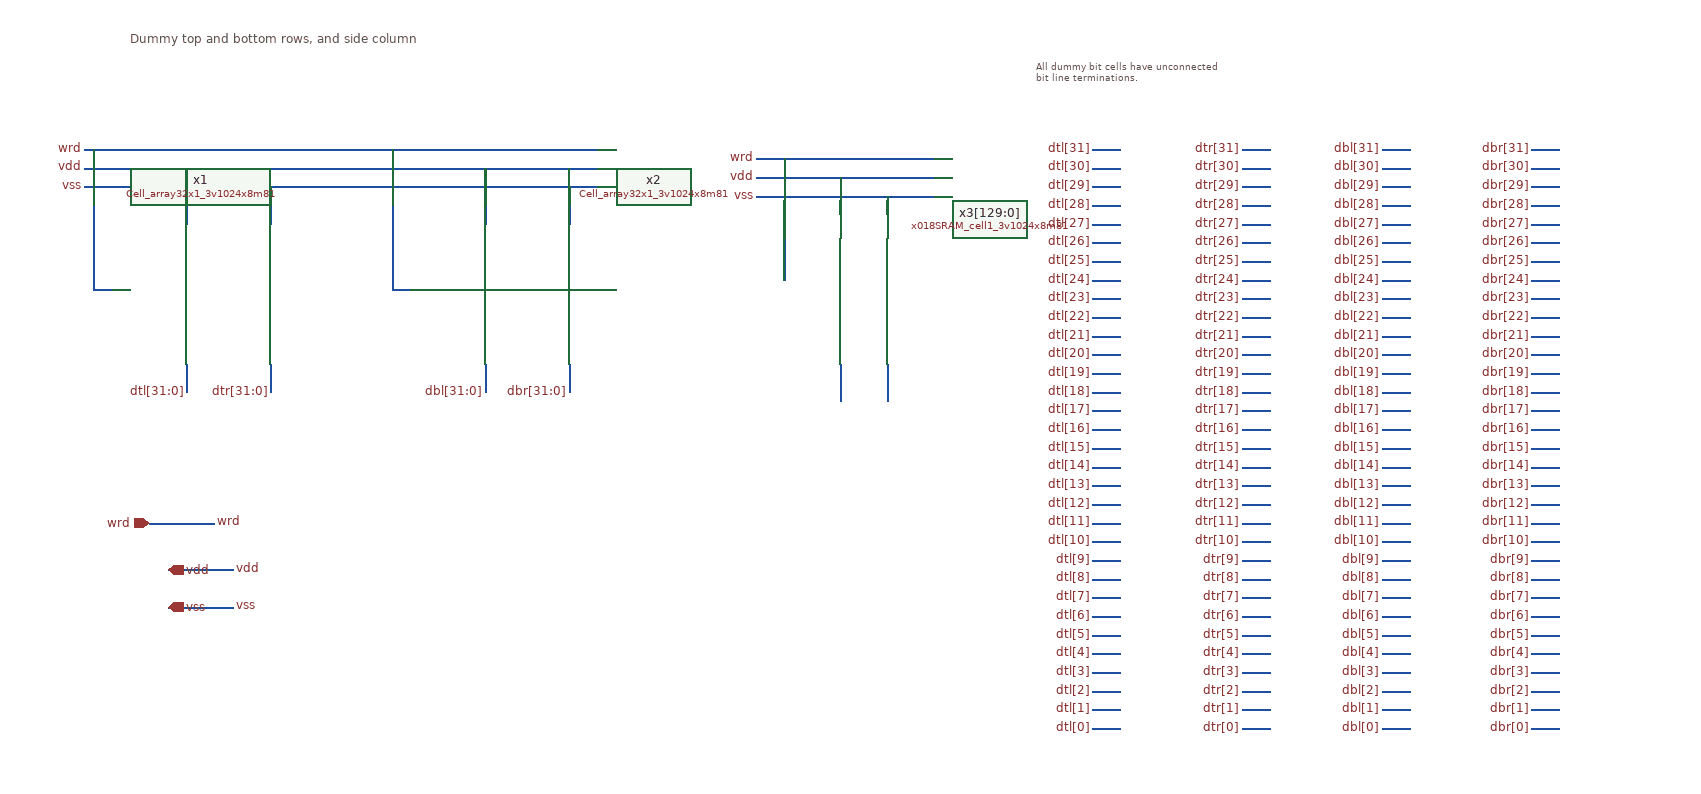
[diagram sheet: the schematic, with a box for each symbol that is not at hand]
v {xschem version=3.4.6 file_version=1.2}
G {}
K {}
V {}
S {}
E {}
T {Dummy top and bottom rows, and side column} -160 -200 0 0 0.4 0.4 {}
T {All dummy bit cells have unconnected
bit line terminations.} 810 -170 0 0 0.3 0.3 {}
N 310 -30 310 10 {lab=vss}
N 220 -50 220 10 {lab=vdd}
N -10 -30 -10 10 {lab=vss}
N -100 -50 -100 10 {lab=vdd}
N -200 80 -180 80 {lab=wrd}
N -200 -70 -200 80 {lab=wrd}
N 120 80 140 80 {lab=wrd}
N 120 -70 120 80 {lab=wrd}
N -100 160 -100 190 {lab=dtl[31:0]}
N -10 160 -10 190 {lab=dtr[31:0]}
N 220 160 220 190 {lab=dbl[31:0]}
N 310 160 310 190 {lab=dbr[31:0]}
N -140 330 -70 330 {lab=wrd}
N -120 380 -50 380 {lab=vdd}
N -120 420 -50 420 {lab=vss}
N -210 -50 340 -50 {lab=vdd}
N -210 -30 340 -30 {lab=vss}
N 540 -60 540 70 {lab=wrd}
N 600 -40 600 0 {lab=vdd}
N 600 160 600 200 {lab=#net1}
N 650 160 650 200 {lab=#net2}
N 510 -20 700 -20 {lab=vss}
N 650 -20 650 0 {lab=vss}
N 510 -40 700 -40 {lab=vdd}
N 510 -60 700 -60 {lab=wrd}
N -210 -70 340 -70 {lab=wrd}
N 870 -70 900 -70 {lab=dtl[31]}
N 870 -50 900 -50 {lab=dtl[30]}
N 870 -30 900 -30 {lab=dtl[29]}
N 870 -10 900 -10 {lab=dtl[28]}
N 870 10 900 10 {lab=dtl[27]}
N 870 30 900 30 {lab=dtl[26]}
N 870 50 900 50 {lab=dtl[25]}
N 870 70 900 70 {lab=dtl[24]}
N 870 90 900 90 {lab=dtl[23]}
N 870 110 900 110 {lab=dtl[22]}
N 870 130 900 130 {lab=dtl[21]}
N 870 150 900 150 {lab=dtl[20]}
N 870 170 900 170 {lab=dtl[19]}
N 870 190 900 190 {lab=dtl[18]}
N 870 210 900 210 {lab=dtl[17]}
N 870 230 900 230 {lab=dtl[16]}
N 870 250 900 250 {lab=dtl[15]}
N 870 270 900 270 {lab=dtl[14]}
N 870 290 900 290 {lab=dtl[13]}
N 870 310 900 310 {lab=dtl[12]}
N 870 330 900 330 {lab=dtl[11]}
N 870 350 900 350 {lab=dtl[10]}
N 870 370 900 370 {lab=dtl[9]}
N 870 390 900 390 {lab=dtl[8]}
N 870 410 900 410 {lab=dtl[7]}
N 870 430 900 430 {lab=dtl[6]}
N 870 450 900 450 {lab=dtl[5]}
N 870 470 900 470 {lab=dtl[4]}
N 870 490 900 490 {lab=dtl[3]}
N 870 510 900 510 {lab=dtl[2]}
N 870 530 900 530 {lab=dtl[1]}
N 870 550 900 550 {lab=dtl[0]}
N 1030 -70 1060 -70 {lab=dtr[31]}
N 1030 -50 1060 -50 {lab=dtr[30]}
N 1030 -30 1060 -30 {lab=dtr[29]}
N 1030 -10 1060 -10 {lab=dtr[28]}
N 1030 10 1060 10 {lab=dtr[27]}
N 1030 30 1060 30 {lab=dtr[26]}
N 1030 50 1060 50 {lab=dtr[25]}
N 1030 70 1060 70 {lab=dtr[24]}
N 1030 90 1060 90 {lab=dtr[23]}
N 1030 110 1060 110 {lab=dtr[22]}
N 1030 130 1060 130 {lab=dtr[21]}
N 1030 150 1060 150 {lab=dtr[20]}
N 1030 170 1060 170 {lab=dtr[19]}
N 1030 190 1060 190 {lab=dtr[18]}
N 1030 210 1060 210 {lab=dtr[17]}
N 1030 230 1060 230 {lab=dtr[16]}
N 1030 250 1060 250 {lab=dtr[15]}
N 1030 270 1060 270 {lab=dtr[14]}
N 1030 290 1060 290 {lab=dtr[13]}
N 1030 310 1060 310 {lab=dtr[12]}
N 1030 330 1060 330 {lab=dtr[11]}
N 1030 350 1060 350 {lab=dtr[10]}
N 1030 370 1060 370 {lab=dtr[9]}
N 1030 390 1060 390 {lab=dtr[8]}
N 1030 410 1060 410 {lab=dtr[7]}
N 1030 430 1060 430 {lab=dtr[6]}
N 1030 450 1060 450 {lab=dtr[5]}
N 1030 470 1060 470 {lab=dtr[4]}
N 1030 490 1060 490 {lab=dtr[3]}
N 1030 510 1060 510 {lab=dtr[2]}
N 1030 530 1060 530 {lab=dtr[1]}
N 1030 550 1060 550 {lab=dtr[0]}
N 1180 -70 1210 -70 {lab=dbl[31]}
N 1180 -50 1210 -50 {lab=dbl[30]}
N 1180 -30 1210 -30 {lab=dbl[29]}
N 1180 -10 1210 -10 {lab=dbl[28]}
N 1180 10 1210 10 {lab=dbl[27]}
N 1180 30 1210 30 {lab=dbl[26]}
N 1180 50 1210 50 {lab=dbl[25]}
N 1180 70 1210 70 {lab=dbl[24]}
N 1180 90 1210 90 {lab=dbl[23]}
N 1180 110 1210 110 {lab=dbl[22]}
N 1180 130 1210 130 {lab=dbl[21]}
N 1180 150 1210 150 {lab=dbl[20]}
N 1180 170 1210 170 {lab=dbl[19]}
N 1180 190 1210 190 {lab=dbl[18]}
N 1180 210 1210 210 {lab=dbl[17]}
N 1180 230 1210 230 {lab=dbl[16]}
N 1180 250 1210 250 {lab=dbl[15]}
N 1180 270 1210 270 {lab=dbl[14]}
N 1180 290 1210 290 {lab=dbl[13]}
N 1180 310 1210 310 {lab=dbl[12]}
N 1180 330 1210 330 {lab=dbl[11]}
N 1180 350 1210 350 {lab=dbl[10]}
N 1180 370 1210 370 {lab=dbl[9]}
N 1180 390 1210 390 {lab=dbl[8]}
N 1180 410 1210 410 {lab=dbl[7]}
N 1180 430 1210 430 {lab=dbl[6]}
N 1180 450 1210 450 {lab=dbl[5]}
N 1180 470 1210 470 {lab=dbl[4]}
N 1180 490 1210 490 {lab=dbl[3]}
N 1180 510 1210 510 {lab=dbl[2]}
N 1180 530 1210 530 {lab=dbl[1]}
N 1180 550 1210 550 {lab=dbl[0]}
N 1340 -70 1370 -70 {lab=dbr[31]}
N 1340 -50 1370 -50 {lab=dbr[30]}
N 1340 -30 1370 -30 {lab=dbr[29]}
N 1340 -10 1370 -10 {lab=dbr[28]}
N 1340 10 1370 10 {lab=dbr[27]}
N 1340 30 1370 30 {lab=dbr[26]}
N 1340 50 1370 50 {lab=dbr[25]}
N 1340 70 1370 70 {lab=dbr[24]}
N 1340 90 1370 90 {lab=dbr[23]}
N 1340 110 1370 110 {lab=dbr[22]}
N 1340 130 1370 130 {lab=dbr[21]}
N 1340 150 1370 150 {lab=dbr[20]}
N 1340 170 1370 170 {lab=dbr[19]}
N 1340 190 1370 190 {lab=dbr[18]}
N 1340 210 1370 210 {lab=dbr[17]}
N 1340 230 1370 230 {lab=dbr[16]}
N 1340 250 1370 250 {lab=dbr[15]}
N 1340 270 1370 270 {lab=dbr[14]}
N 1340 290 1370 290 {lab=dbr[13]}
N 1340 310 1370 310 {lab=dbr[12]}
N 1340 330 1370 330 {lab=dbr[11]}
N 1340 350 1370 350 {lab=dbr[10]}
N 1340 370 1370 370 {lab=dbr[9]}
N 1340 390 1370 390 {lab=dbr[8]}
N 1340 410 1370 410 {lab=dbr[7]}
N 1340 430 1370 430 {lab=dbr[6]}
N 1340 450 1370 450 {lab=dbr[5]}
N 1340 470 1370 470 {lab=dbr[4]}
N 1340 490 1370 490 {lab=dbr[3]}
N 1340 510 1370 510 {lab=dbr[2]}
N 1340 530 1370 530 {lab=dbr[1]}
N 1340 550 1370 550 {lab=dbr[0]}
C {Cell_array32x1_3v1024x8m81.sym} -50 80 0 0 {name=x1}
C {Cell_array32x1_3v1024x8m81.sym} 270 80 0 0 {name=x2}
C {lab_pin.sym} -210 -50 0 0 {name=p97 sig_type=std_logic lab=vdd}
C {lab_pin.sym} -210 -30 0 0 {name=p98 sig_type=std_logic lab=vss}
C {ipin.sym} -140 330 0 0 {name=p105 lab=wrd}
C {iopin.sym} -120 380 0 1 {name=p108 lab=vdd}
C {iopin.sym} -120 420 0 1 {name=p109 lab=vss}
C {lab_pin.sym} -50 420 0 1 {name=p110 sig_type=std_logic lab=vss}
C {lab_pin.sym} -50 380 0 1 {name=p111 sig_type=std_logic lab=vdd}
C {lab_pin.sym} -70 330 0 1 {name=p114 sig_type=std_logic lab=wrd}
C {x018SRAM_cell1_3v1024x8m81.sym} 690 50 0 0 {name=x3[129:0]}
C {lab_pin.sym} 510 -20 0 0 {name=p5 sig_type=std_logic lab=vss}
C {lab_pin.sym} 510 -40 0 0 {name=p6 sig_type=std_logic lab=vdd}
C {lab_pin.sym} 510 -60 0 0 {name=p9 sig_type=std_logic lab=wrd}
C {lab_pin.sym} -210 -70 0 0 {name=p10 sig_type=std_logic lab=wrd}
C {noconn.sym} 650 200 3 0 {name=l1}
C {noconn.sym} 600 200 3 0 {name=l2}
C {lab_pin.sym} -100 190 3 0 {name=p1 sig_type=std_logic lab=dtl[31:0]}
C {lab_pin.sym} -10 190 3 0 {name=p2 sig_type=std_logic lab=dtr[31:0]}
C {lab_pin.sym} 220 190 3 0 {name=p3 sig_type=std_logic lab=dbl[31:0]}
C {lab_pin.sym} 310 190 3 0 {name=p4 sig_type=std_logic lab=dbr[31:0]}
C {noconn.sym} 900 -70 0 1 {name=l3}
C {noconn.sym} 900 -50 0 1 {name=l4}
C {noconn.sym} 900 -30 0 1 {name=l5}
C {noconn.sym} 900 -10 0 1 {name=l6}
C {noconn.sym} 900 10 0 1 {name=l7}
C {noconn.sym} 900 30 0 1 {name=l8}
C {noconn.sym} 900 50 0 1 {name=l9}
C {noconn.sym} 900 70 0 1 {name=l10}
C {noconn.sym} 900 90 0 1 {name=l11}
C {noconn.sym} 900 110 0 1 {name=l12}
C {noconn.sym} 900 130 0 1 {name=l13}
C {noconn.sym} 900 150 0 1 {name=l14}
C {noconn.sym} 900 170 0 1 {name=l15}
C {noconn.sym} 900 190 0 1 {name=l16}
C {noconn.sym} 900 210 0 1 {name=l17}
C {noconn.sym} 900 230 0 1 {name=l18}
C {noconn.sym} 900 250 0 1 {name=l19}
C {noconn.sym} 900 270 0 1 {name=l20}
C {noconn.sym} 900 290 0 1 {name=l21}
C {noconn.sym} 900 310 0 1 {name=l22}
C {noconn.sym} 900 330 0 1 {name=l23}
C {noconn.sym} 900 350 0 1 {name=l24}
C {noconn.sym} 900 370 0 1 {name=l25}
C {noconn.sym} 900 390 0 1 {name=l26}
C {noconn.sym} 900 410 0 1 {name=l27}
C {noconn.sym} 900 430 0 1 {name=l28}
C {noconn.sym} 900 450 0 1 {name=l29}
C {noconn.sym} 900 470 0 1 {name=l30}
C {noconn.sym} 900 490 0 1 {name=l31}
C {noconn.sym} 900 510 0 1 {name=l32}
C {noconn.sym} 900 530 0 1 {name=l33}
C {noconn.sym} 900 550 0 1 {name=l34}
C {lab_pin.sym} 870 -70 0 0 {name=p7 sig_type=std_logic lab=dtl[31]}
C {lab_pin.sym} 870 -50 0 0 {name=p8 sig_type=std_logic lab=dtl[30]}
C {lab_pin.sym} 870 -30 0 0 {name=p11 sig_type=std_logic lab=dtl[29]}
C {lab_pin.sym} 870 -10 0 0 {name=p12 sig_type=std_logic lab=dtl[28]}
C {lab_pin.sym} 870 10 0 0 {name=p13 sig_type=std_logic lab=dtl[27]}
C {lab_pin.sym} 870 30 0 0 {name=p14 sig_type=std_logic lab=dtl[26]}
C {lab_pin.sym} 870 50 0 0 {name=p15 sig_type=std_logic lab=dtl[25]}
C {lab_pin.sym} 870 70 0 0 {name=p16 sig_type=std_logic lab=dtl[24]}
C {lab_pin.sym} 870 90 0 0 {name=p17 sig_type=std_logic lab=dtl[23]}
C {lab_pin.sym} 870 110 0 0 {name=p18 sig_type=std_logic lab=dtl[22]}
C {lab_pin.sym} 870 130 0 0 {name=p19 sig_type=std_logic lab=dtl[21]}
C {lab_pin.sym} 870 150 0 0 {name=p20 sig_type=std_logic lab=dtl[20]}
C {lab_pin.sym} 870 170 0 0 {name=p21 sig_type=std_logic lab=dtl[19]}
C {lab_pin.sym} 870 190 0 0 {name=p22 sig_type=std_logic lab=dtl[18]}
C {lab_pin.sym} 870 210 0 0 {name=p23 sig_type=std_logic lab=dtl[17]}
C {lab_pin.sym} 870 230 0 0 {name=p24 sig_type=std_logic lab=dtl[16]}
C {lab_pin.sym} 870 250 0 0 {name=p25 sig_type=std_logic lab=dtl[15]}
C {lab_pin.sym} 870 270 0 0 {name=p26 sig_type=std_logic lab=dtl[14]}
C {lab_pin.sym} 870 290 0 0 {name=p27 sig_type=std_logic lab=dtl[13]}
C {lab_pin.sym} 870 310 0 0 {name=p28 sig_type=std_logic lab=dtl[12]}
C {lab_pin.sym} 870 330 0 0 {name=p29 sig_type=std_logic lab=dtl[11]}
C {lab_pin.sym} 870 350 0 0 {name=p30 sig_type=std_logic lab=dtl[10]}
C {lab_pin.sym} 870 370 0 0 {name=p31 sig_type=std_logic lab=dtl[9]}
C {lab_pin.sym} 870 390 0 0 {name=p32 sig_type=std_logic lab=dtl[8]}
C {lab_pin.sym} 870 410 0 0 {name=p33 sig_type=std_logic lab=dtl[7]}
C {lab_pin.sym} 870 430 0 0 {name=p34 sig_type=std_logic lab=dtl[6]}
C {lab_pin.sym} 870 450 0 0 {name=p35 sig_type=std_logic lab=dtl[5]}
C {lab_pin.sym} 870 470 0 0 {name=p36 sig_type=std_logic lab=dtl[4]}
C {lab_pin.sym} 870 490 0 0 {name=p37 sig_type=std_logic lab=dtl[3]}
C {lab_pin.sym} 870 510 0 0 {name=p38 sig_type=std_logic lab=dtl[2]}
C {lab_pin.sym} 870 530 0 0 {name=p39 sig_type=std_logic lab=dtl[1]}
C {lab_pin.sym} 870 550 0 0 {name=p40 sig_type=std_logic lab=dtl[0]}
C {noconn.sym} 1060 -70 0 1 {name=l35}
C {noconn.sym} 1060 -50 0 1 {name=l36}
C {noconn.sym} 1060 -30 0 1 {name=l37}
C {noconn.sym} 1060 -10 0 1 {name=l38}
C {noconn.sym} 1060 10 0 1 {name=l39}
C {noconn.sym} 1060 30 0 1 {name=l40}
C {noconn.sym} 1060 50 0 1 {name=l41}
C {noconn.sym} 1060 70 0 1 {name=l42}
C {noconn.sym} 1060 90 0 1 {name=l43}
C {noconn.sym} 1060 110 0 1 {name=l44}
C {noconn.sym} 1060 130 0 1 {name=l45}
C {noconn.sym} 1060 150 0 1 {name=l46}
C {noconn.sym} 1060 170 0 1 {name=l47}
C {noconn.sym} 1060 190 0 1 {name=l48}
C {noconn.sym} 1060 210 0 1 {name=l49}
C {noconn.sym} 1060 230 0 1 {name=l50}
C {noconn.sym} 1060 250 0 1 {name=l51}
C {noconn.sym} 1060 270 0 1 {name=l52}
C {noconn.sym} 1060 290 0 1 {name=l53}
C {noconn.sym} 1060 310 0 1 {name=l54}
C {noconn.sym} 1060 330 0 1 {name=l55}
C {noconn.sym} 1060 350 0 1 {name=l56}
C {noconn.sym} 1060 370 0 1 {name=l57}
C {noconn.sym} 1060 390 0 1 {name=l58}
C {noconn.sym} 1060 410 0 1 {name=l59}
C {noconn.sym} 1060 430 0 1 {name=l60}
C {noconn.sym} 1060 450 0 1 {name=l61}
C {noconn.sym} 1060 470 0 1 {name=l62}
C {noconn.sym} 1060 490 0 1 {name=l63}
C {noconn.sym} 1060 510 0 1 {name=l64}
C {noconn.sym} 1060 530 0 1 {name=l65}
C {noconn.sym} 1060 550 0 1 {name=l66}
C {lab_pin.sym} 1030 -70 0 0 {name=p41 sig_type=std_logic lab=dtr[31]}
C {lab_pin.sym} 1030 -50 0 0 {name=p42 sig_type=std_logic lab=dtr[30]}
C {lab_pin.sym} 1030 -30 0 0 {name=p43 sig_type=std_logic lab=dtr[29]}
C {lab_pin.sym} 1030 -10 0 0 {name=p44 sig_type=std_logic lab=dtr[28]}
C {lab_pin.sym} 1030 10 0 0 {name=p45 sig_type=std_logic lab=dtr[27]}
C {lab_pin.sym} 1030 30 0 0 {name=p46 sig_type=std_logic lab=dtr[26]}
C {lab_pin.sym} 1030 50 0 0 {name=p47 sig_type=std_logic lab=dtr[25]}
C {lab_pin.sym} 1030 70 0 0 {name=p48 sig_type=std_logic lab=dtr[24]}
C {lab_pin.sym} 1030 90 0 0 {name=p49 sig_type=std_logic lab=dtr[23]}
C {lab_pin.sym} 1030 110 0 0 {name=p50 sig_type=std_logic lab=dtr[22]}
C {lab_pin.sym} 1030 130 0 0 {name=p51 sig_type=std_logic lab=dtr[21]}
C {lab_pin.sym} 1030 150 0 0 {name=p52 sig_type=std_logic lab=dtr[20]}
C {lab_pin.sym} 1030 170 0 0 {name=p53 sig_type=std_logic lab=dtr[19]}
C {lab_pin.sym} 1030 190 0 0 {name=p54 sig_type=std_logic lab=dtr[18]}
C {lab_pin.sym} 1030 210 0 0 {name=p55 sig_type=std_logic lab=dtr[17]}
C {lab_pin.sym} 1030 230 0 0 {name=p56 sig_type=std_logic lab=dtr[16]}
C {lab_pin.sym} 1030 250 0 0 {name=p57 sig_type=std_logic lab=dtr[15]}
C {lab_pin.sym} 1030 270 0 0 {name=p58 sig_type=std_logic lab=dtr[14]}
C {lab_pin.sym} 1030 290 0 0 {name=p59 sig_type=std_logic lab=dtr[13]}
C {lab_pin.sym} 1030 310 0 0 {name=p60 sig_type=std_logic lab=dtr[12]}
C {lab_pin.sym} 1030 330 0 0 {name=p61 sig_type=std_logic lab=dtr[11]}
C {lab_pin.sym} 1030 350 0 0 {name=p62 sig_type=std_logic lab=dtr[10]}
C {lab_pin.sym} 1030 370 0 0 {name=p63 sig_type=std_logic lab=dtr[9]}
C {lab_pin.sym} 1030 390 0 0 {name=p64 sig_type=std_logic lab=dtr[8]}
C {lab_pin.sym} 1030 410 0 0 {name=p65 sig_type=std_logic lab=dtr[7]}
C {lab_pin.sym} 1030 430 0 0 {name=p66 sig_type=std_logic lab=dtr[6]}
C {lab_pin.sym} 1030 450 0 0 {name=p67 sig_type=std_logic lab=dtr[5]}
C {lab_pin.sym} 1030 470 0 0 {name=p68 sig_type=std_logic lab=dtr[4]}
C {lab_pin.sym} 1030 490 0 0 {name=p69 sig_type=std_logic lab=dtr[3]}
C {lab_pin.sym} 1030 510 0 0 {name=p70 sig_type=std_logic lab=dtr[2]}
C {lab_pin.sym} 1030 530 0 0 {name=p71 sig_type=std_logic lab=dtr[1]}
C {lab_pin.sym} 1030 550 0 0 {name=p72 sig_type=std_logic lab=dtr[0]}
C {noconn.sym} 1210 -70 0 1 {name=l67}
C {noconn.sym} 1210 -50 0 1 {name=l68}
C {noconn.sym} 1210 -30 0 1 {name=l69}
C {noconn.sym} 1210 -10 0 1 {name=l70}
C {noconn.sym} 1210 10 0 1 {name=l71}
C {noconn.sym} 1210 30 0 1 {name=l72}
C {noconn.sym} 1210 50 0 1 {name=l73}
C {noconn.sym} 1210 70 0 1 {name=l74}
C {noconn.sym} 1210 90 0 1 {name=l75}
C {noconn.sym} 1210 110 0 1 {name=l76}
C {noconn.sym} 1210 130 0 1 {name=l77}
C {noconn.sym} 1210 150 0 1 {name=l78}
C {noconn.sym} 1210 170 0 1 {name=l79}
C {noconn.sym} 1210 190 0 1 {name=l80}
C {noconn.sym} 1210 210 0 1 {name=l81}
C {noconn.sym} 1210 230 0 1 {name=l82}
C {noconn.sym} 1210 250 0 1 {name=l83}
C {noconn.sym} 1210 270 0 1 {name=l84}
C {noconn.sym} 1210 290 0 1 {name=l85}
C {noconn.sym} 1210 310 0 1 {name=l86}
C {noconn.sym} 1210 330 0 1 {name=l87}
C {noconn.sym} 1210 350 0 1 {name=l88}
C {noconn.sym} 1210 370 0 1 {name=l89}
C {noconn.sym} 1210 390 0 1 {name=l90}
C {noconn.sym} 1210 410 0 1 {name=l91}
C {noconn.sym} 1210 430 0 1 {name=l92}
C {noconn.sym} 1210 450 0 1 {name=l93}
C {noconn.sym} 1210 470 0 1 {name=l94}
C {noconn.sym} 1210 490 0 1 {name=l95}
C {noconn.sym} 1210 510 0 1 {name=l96}
C {noconn.sym} 1210 530 0 1 {name=l97}
C {noconn.sym} 1210 550 0 1 {name=l98}
C {lab_pin.sym} 1180 -70 0 0 {name=p73 sig_type=std_logic lab=dbl[31]}
C {lab_pin.sym} 1180 -50 0 0 {name=p74 sig_type=std_logic lab=dbl[30]}
C {lab_pin.sym} 1180 -30 0 0 {name=p75 sig_type=std_logic lab=dbl[29]}
C {lab_pin.sym} 1180 -10 0 0 {name=p76 sig_type=std_logic lab=dbl[28]}
C {lab_pin.sym} 1180 10 0 0 {name=p77 sig_type=std_logic lab=dbl[27]}
C {lab_pin.sym} 1180 30 0 0 {name=p78 sig_type=std_logic lab=dbl[26]}
C {lab_pin.sym} 1180 50 0 0 {name=p79 sig_type=std_logic lab=dbl[25]}
C {lab_pin.sym} 1180 70 0 0 {name=p80 sig_type=std_logic lab=dbl[24]}
C {lab_pin.sym} 1180 90 0 0 {name=p81 sig_type=std_logic lab=dbl[23]}
C {lab_pin.sym} 1180 110 0 0 {name=p82 sig_type=std_logic lab=dbl[22]}
C {lab_pin.sym} 1180 130 0 0 {name=p83 sig_type=std_logic lab=dbl[21]}
C {lab_pin.sym} 1180 150 0 0 {name=p84 sig_type=std_logic lab=dbl[20]}
C {lab_pin.sym} 1180 170 0 0 {name=p85 sig_type=std_logic lab=dbl[19]}
C {lab_pin.sym} 1180 190 0 0 {name=p86 sig_type=std_logic lab=dbl[18]}
C {lab_pin.sym} 1180 210 0 0 {name=p87 sig_type=std_logic lab=dbl[17]}
C {lab_pin.sym} 1180 230 0 0 {name=p88 sig_type=std_logic lab=dbl[16]}
C {lab_pin.sym} 1180 250 0 0 {name=p89 sig_type=std_logic lab=dbl[15]}
C {lab_pin.sym} 1180 270 0 0 {name=p90 sig_type=std_logic lab=dbl[14]}
C {lab_pin.sym} 1180 290 0 0 {name=p91 sig_type=std_logic lab=dbl[13]}
C {lab_pin.sym} 1180 310 0 0 {name=p92 sig_type=std_logic lab=dbl[12]}
C {lab_pin.sym} 1180 330 0 0 {name=p93 sig_type=std_logic lab=dbl[11]}
C {lab_pin.sym} 1180 350 0 0 {name=p94 sig_type=std_logic lab=dbl[10]}
C {lab_pin.sym} 1180 370 0 0 {name=p95 sig_type=std_logic lab=dbl[9]}
C {lab_pin.sym} 1180 390 0 0 {name=p96 sig_type=std_logic lab=dbl[8]}
C {lab_pin.sym} 1180 410 0 0 {name=p99 sig_type=std_logic lab=dbl[7]}
C {lab_pin.sym} 1180 430 0 0 {name=p100 sig_type=std_logic lab=dbl[6]}
C {lab_pin.sym} 1180 450 0 0 {name=p101 sig_type=std_logic lab=dbl[5]}
C {lab_pin.sym} 1180 470 0 0 {name=p102 sig_type=std_logic lab=dbl[4]}
C {lab_pin.sym} 1180 490 0 0 {name=p103 sig_type=std_logic lab=dbl[3]}
C {lab_pin.sym} 1180 510 0 0 {name=p104 sig_type=std_logic lab=dbl[2]}
C {lab_pin.sym} 1180 530 0 0 {name=p106 sig_type=std_logic lab=dbl[1]}
C {lab_pin.sym} 1180 550 0 0 {name=p107 sig_type=std_logic lab=dbl[0]}
C {noconn.sym} 1370 -70 0 1 {name=l99}
C {noconn.sym} 1370 -50 0 1 {name=l100}
C {noconn.sym} 1370 -30 0 1 {name=l101}
C {noconn.sym} 1370 -10 0 1 {name=l102}
C {noconn.sym} 1370 10 0 1 {name=l103}
C {noconn.sym} 1370 30 0 1 {name=l104}
C {noconn.sym} 1370 50 0 1 {name=l105}
C {noconn.sym} 1370 70 0 1 {name=l106}
C {noconn.sym} 1370 90 0 1 {name=l107}
C {noconn.sym} 1370 110 0 1 {name=l108}
C {noconn.sym} 1370 130 0 1 {name=l109}
C {noconn.sym} 1370 150 0 1 {name=l110}
C {noconn.sym} 1370 170 0 1 {name=l111}
C {noconn.sym} 1370 190 0 1 {name=l112}
C {noconn.sym} 1370 210 0 1 {name=l113}
C {noconn.sym} 1370 230 0 1 {name=l114}
C {noconn.sym} 1370 250 0 1 {name=l115}
C {noconn.sym} 1370 270 0 1 {name=l116}
C {noconn.sym} 1370 290 0 1 {name=l117}
C {noconn.sym} 1370 310 0 1 {name=l118}
C {noconn.sym} 1370 330 0 1 {name=l119}
C {noconn.sym} 1370 350 0 1 {name=l120}
C {noconn.sym} 1370 370 0 1 {name=l121}
C {noconn.sym} 1370 390 0 1 {name=l122}
C {noconn.sym} 1370 410 0 1 {name=l123}
C {noconn.sym} 1370 430 0 1 {name=l124}
C {noconn.sym} 1370 450 0 1 {name=l125}
C {noconn.sym} 1370 470 0 1 {name=l126}
C {noconn.sym} 1370 490 0 1 {name=l127}
C {noconn.sym} 1370 510 0 1 {name=l128}
C {noconn.sym} 1370 530 0 1 {name=l129}
C {noconn.sym} 1370 550 0 1 {name=l130}
C {lab_pin.sym} 1340 -70 0 0 {name=p112 sig_type=std_logic lab=dbr[31]}
C {lab_pin.sym} 1340 -50 0 0 {name=p113 sig_type=std_logic lab=dbr[30]}
C {lab_pin.sym} 1340 -30 0 0 {name=p115 sig_type=std_logic lab=dbr[29]}
C {lab_pin.sym} 1340 -10 0 0 {name=p116 sig_type=std_logic lab=dbr[28]}
C {lab_pin.sym} 1340 10 0 0 {name=p117 sig_type=std_logic lab=dbr[27]}
C {lab_pin.sym} 1340 30 0 0 {name=p118 sig_type=std_logic lab=dbr[26]}
C {lab_pin.sym} 1340 50 0 0 {name=p119 sig_type=std_logic lab=dbr[25]}
C {lab_pin.sym} 1340 70 0 0 {name=p120 sig_type=std_logic lab=dbr[24]}
C {lab_pin.sym} 1340 90 0 0 {name=p121 sig_type=std_logic lab=dbr[23]}
C {lab_pin.sym} 1340 110 0 0 {name=p122 sig_type=std_logic lab=dbr[22]}
C {lab_pin.sym} 1340 130 0 0 {name=p123 sig_type=std_logic lab=dbr[21]}
C {lab_pin.sym} 1340 150 0 0 {name=p124 sig_type=std_logic lab=dbr[20]}
C {lab_pin.sym} 1340 170 0 0 {name=p125 sig_type=std_logic lab=dbr[19]}
C {lab_pin.sym} 1340 190 0 0 {name=p126 sig_type=std_logic lab=dbr[18]}
C {lab_pin.sym} 1340 210 0 0 {name=p127 sig_type=std_logic lab=dbr[17]}
C {lab_pin.sym} 1340 230 0 0 {name=p128 sig_type=std_logic lab=dbr[16]}
C {lab_pin.sym} 1340 250 0 0 {name=p129 sig_type=std_logic lab=dbr[15]}
C {lab_pin.sym} 1340 270 0 0 {name=p130 sig_type=std_logic lab=dbr[14]}
C {lab_pin.sym} 1340 290 0 0 {name=p131 sig_type=std_logic lab=dbr[13]}
C {lab_pin.sym} 1340 310 0 0 {name=p132 sig_type=std_logic lab=dbr[12]}
C {lab_pin.sym} 1340 330 0 0 {name=p133 sig_type=std_logic lab=dbr[11]}
C {lab_pin.sym} 1340 350 0 0 {name=p134 sig_type=std_logic lab=dbr[10]}
C {lab_pin.sym} 1340 370 0 0 {name=p135 sig_type=std_logic lab=dbr[9]}
C {lab_pin.sym} 1340 390 0 0 {name=p136 sig_type=std_logic lab=dbr[8]}
C {lab_pin.sym} 1340 410 0 0 {name=p137 sig_type=std_logic lab=dbr[7]}
C {lab_pin.sym} 1340 430 0 0 {name=p138 sig_type=std_logic lab=dbr[6]}
C {lab_pin.sym} 1340 450 0 0 {name=p139 sig_type=std_logic lab=dbr[5]}
C {lab_pin.sym} 1340 470 0 0 {name=p140 sig_type=std_logic lab=dbr[4]}
C {lab_pin.sym} 1340 490 0 0 {name=p141 sig_type=std_logic lab=dbr[3]}
C {lab_pin.sym} 1340 510 0 0 {name=p142 sig_type=std_logic lab=dbr[2]}
C {lab_pin.sym} 1340 530 0 0 {name=p143 sig_type=std_logic lab=dbr[1]}
C {lab_pin.sym} 1340 550 0 0 {name=p144 sig_type=std_logic lab=dbr[0]}
